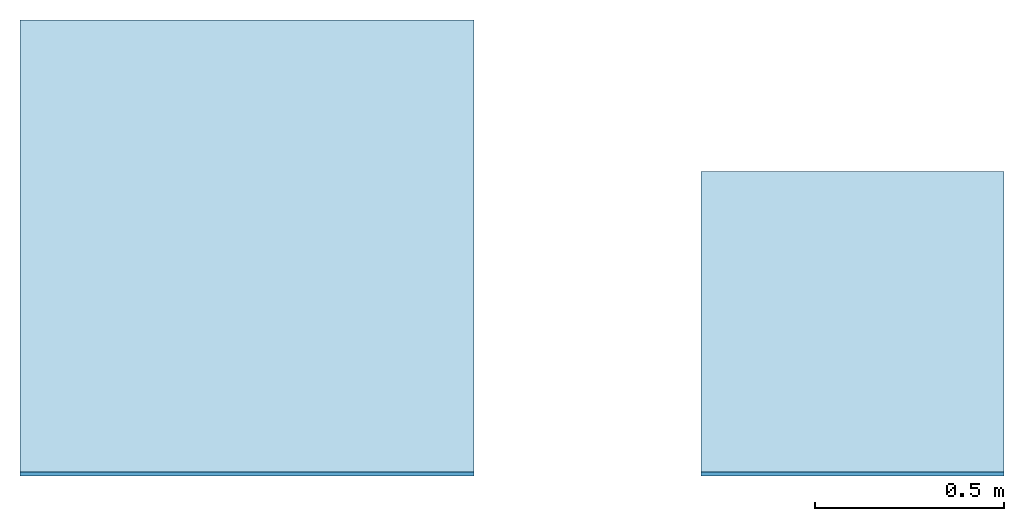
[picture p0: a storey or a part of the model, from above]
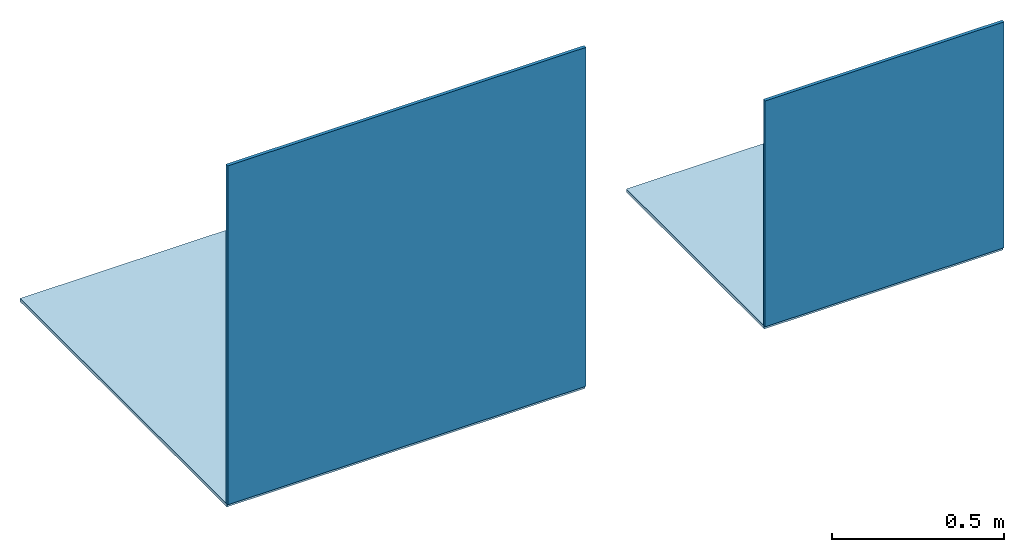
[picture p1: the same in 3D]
Properties of the parts of a building model (IFC2X3)

# File
Description: ViewDefinition [CoordinationView_V2.0]
File name: Número de proyecto
Time: 2018-01-24T15:02:07
Written by: The EXPRESS Data Manager Version 5.02.0100.07 : 28 Aug 2013
Made in: 20140606_1530(x64) - Exporter 15.7.0.0 - Alternate UI 15.7.0.0
Comment: STEP Physical File produced by: The EXPRESS Data Manager Version 5.02.0100.07 : 28 Aug 2013 * Module: EDMstepFileFactory/EDMstandAlone * Creation date: Wed Jan 24 15:02:07 2018 * Host: WEB2 * Database: C:\Users\webpc2\AppData\Local\Temp\{95DA9E5B-3847-4D98-BC87-8018BCFD7E77}\ifc * Database version: 5507 * Database creation date: Wed Jan 24 15:02:07 2018 * Schema: IFC2X3 * Model: DataRepository.ifc * Model creation date: Wed Jan 24 15:02:07 2018 * Header model: DataRepository.ifc_HeaderModel * Header model creation date: Wed Jan 24 15:02:07 2018 * EDMuser: sdai-user * EDMgroup: sdai-group * License ID and type: 5605 : Permanent license. Expiry date: * EDMstepFileFactory options: 020000

# IfcProject, Número de proyecto
LongName: Nombre de proyecto; Phase: Estado de proyecto

# IfcSite, Default
RefLatitude: 40, 25, 0, 86975; RefLongitude: -3, -42, -1, -243858; RefElevation: 0 m

# IfcBuilding
Pset_BuildingCommon - NumberOfStoreys: 1

# IfcBuildingStorey, INARI FLOOR TILES
LongName: INARI FLOOR TILES; Elevation: 0 m

# IfcSlab: Suelo:VIVES - INARI-R NIEVE 120x120, Suelo:VIVES - INARI-R NIEVE 120x120:247554
In: INARI FLOOR TILES
PredefinedType: FLOOR; Material: VIVES - INARI-R NIEVE 120x120 0.011 m
Pset_SlabCommon - Reference: VIVES - INARI-R NIEVE 120x120; LoadBearing: no; IsExternal: no; ThermalTransmittance: 136.364 kg/K/s3; PitchAngle: 0 deg
Pset_ManufacturerTypeInformation - Manufacturer: VIVES Azulejos y Gres S.A.

# IfcSlab: Suelo:VIVES - INARI-R NIEVE 80x80, Suelo:VIVES - INARI-R NIEVE 80x80:247594
In: INARI FLOOR TILES
PredefinedType: FLOOR; Material: VIVES - INARI-R NIEVE 80x80 0.011 m
Pset_SlabCommon - LoadBearing: no; IsExternal: no; PitchAngle: 0 deg; Reference: VIVES - INARI-R NIEVE 80x80; ThermalTransmittance: 136.364 kg/K/s3
Pset_ManufacturerTypeInformation - Manufacturer: VIVES Azulejos y Gres S.A.

# IfcWallStandardCase: Muro básico:VIVES - INARI-R NIEVE 120x120, Muro básico:VIVES - INARI-R NIEVE 120x120:247544
In: INARI FLOOR TILES
Type - PredefinedType: STANDARD; Material: VIVES - INARI-R NIEVE 120x120 0.011 m
Pset_WallCommon - Reference: VIVES - INARI-R NIEVE 120x120; LoadBearing: no; ExtendToStructure: no; IsExternal: no; ThermalTransmittance: 136.364 kg/K/s3
Pset_ManufacturerTypeInformation - Manufacturer: VIVES Azulejos y Gres S.A.

# IfcWallStandardCase: Muro básico:VIVES - INARI-R NIEVE 80x80, Muro básico:VIVES - INARI-R NIEVE 80x80:247584
In: INARI FLOOR TILES
Type - PredefinedType: STANDARD; Material: VIVES - INARI-R NIEVE 80x80 0.011 m
Pset_WallCommon - LoadBearing: no; ExtendToStructure: no; IsExternal: no; Reference: VIVES - INARI-R NIEVE 80x80; ThermalTransmittance: 136.364 kg/K/s3
Pset_ManufacturerTypeInformation - Manufacturer: VIVES Azulejos y Gres S.A.
